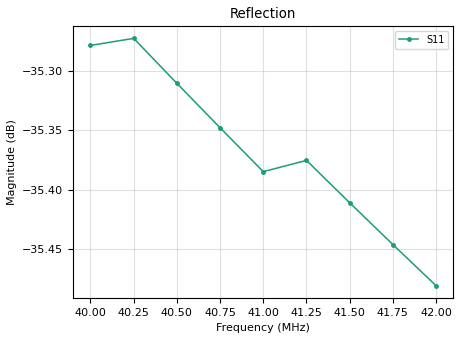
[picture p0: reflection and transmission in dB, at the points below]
# Hz S RI R 50
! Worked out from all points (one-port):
!   9 points, 40 MHz to 42 MHz, reference 50 ohm
!   lowest |S11| = -35.5 dB at 42 MHz (marker M1), VSWR 1.03, Z = 50.7 - j1.55 ohm
!   |S11| at or under -10 dB: start of sweep to end of sweep
4e7  0.00828 -0.0151
4.025e7  0.00812 -0.0152
4.05e7  0.00796 -0.0152
4.075e7  0.0078 -0.0152
4.1e7  0.00764 -0.0152
4.125e7  0.00748 -0.0153
4.15e7  0.00732 -0.0153
4.175e7  0.00716 -0.0153
4.2e7  0.007 -0.0153
